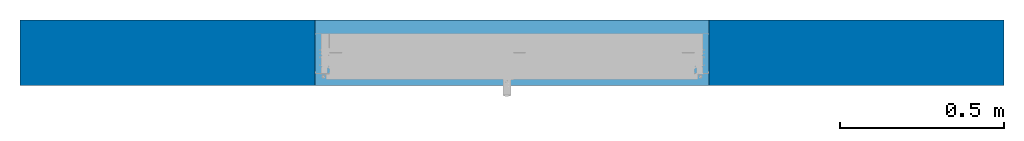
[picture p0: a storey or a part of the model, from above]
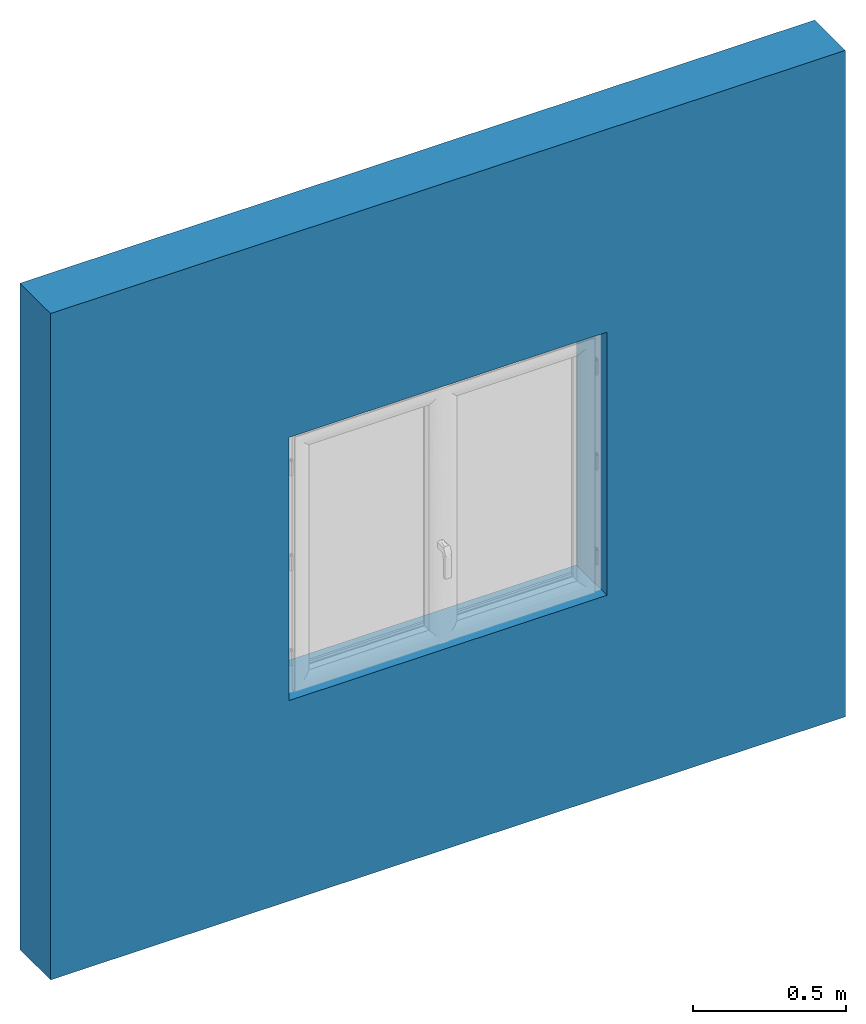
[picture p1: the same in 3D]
Properties of the parts of a building model (IFC2X3)

# File
Description: ViewDefinition [CoordinationView]
Time: 2016-06-16T14:24:24
Written by: Autodesk Revit Architecture 2011 - 1.0
Made in: 20100326_1700(x64)

# IfcSite, 默认
RefLatitude: 42, 24, 53, 508911; RefLongitude: -71, -15, -29, -58837; RefElevation: 0 mm

# IfcBuilding
Pset_BuildingCommon - NumberOfStoreys: 1

# IfcBuildingStorey, Level 1
Elevation: 0 mm
PSet_Revit_标识数据 - 名称: Level 1
PSet_Revit_限制条件 - 立面: 0 mm
PSet_Revit_Type_图形 - 线宽: 1; 颜色: 0; 线型图案: 实心; 端点 1 处的默认符号: no; 端点 2 处的默认符号: yes
PSet_Revit_Type_限制条件 - 基面: 0
PSet_Revit_Type_尺寸标注 - 自动计算房间高度: yes

# IfcWallStandardCase: 基本墙:Wall 1:1320, 基本墙:Wall 1:13409
In: Level 1
Material: 4ITR-20-4 argon inter TGI 200 mm
Pset_WallCommon - Reference: 基本墙:Wall 1; LoadBearing: no; ExtendToStructure: no; IsExternal: yes
PSet_Revit_限制条件 - 定位线: 0; 基准限制条件: Level 1; 底部偏移: 0 mm; 已附着底部: no; 底部延伸距离: 0 mm; 无连接高度: 2659.66 mm; 顶部偏移: 0 mm; 已附着顶部: no; 顶部延伸距离: 0 mm; 房间边界: yes; 与体量相关: no
PSet_Revit_阶段化 - 创建的阶段: New Construction
PSet_Revit_结构 - 结构用途: 0
PSet_Revit_尺寸标注 - 长度: 3000 mm; 面积: 6718965 mm2; 体积: 1343793021 mm3
PSet_Revit_Type_构造 - 在插入点包络: 0; 在端点包络: 0; 宽度: 200 mm; 功能: 1
PSet_Revit_Type_图形 - 粗略比例填充颜色: 0

# IfcWindow: Fenêtre 2 vantaux 1050 x 1200 mm Claire, Huet Fenêtre 2 vantaux Stylium:Fenêtre 2 vantaux 1050 x 1200 mm Claire:Fenêtre 2 vantaux 1050 x 1200 mm Claire:18678
In: Level 1
Type - ParameterTakesPrecedence: no; Sizeable: no
OverallHeight: 1050 mm; OverallWidth: 1200 mm
Pset_WindowCommon - Reference: Huet Fenêtre 2 vantaux Stylium:Fenêtre 2 vantaux 1050 x 1200 mm Claire; IsExternal: yes
PSet_Revit_限制条件 - 标高: Level 1; 底高度: 800 mm
PSet_Revit_其他 - 顶高度: 1850 mm
PSet_Revit_标识数据 - 标记: 1
PSet_Revit_阶段化 - 创建的阶段: New Construction
PSet_Revit_Type_分析模型 - Uw: 1,5; Ug: 1,1; Tlw: 0,54; Condition été Sw: 0,42; Condition été Sw1: 0,39; Condition été Sw2: 0,03; Condition été Sw3: 0,00; Condition hiver Sw: 0,42; Condition hiver Sw1: 0,39; Condition hiver Sw2: 0,03; Condition hiver Sw3: 0,00
PSet_Revit_Type_标识数据 - URL: www.huet.fr; Tél.: 00 33 (0)2 28 12 04 20; 类型注释: Fabriquant de Menuiseries Exterieures, HUET vous offre une large gamme de Fenetres et Porte-Fenetres permettant d’appréhender les différents segments de marché.; Personnalisation: Elargisseur serrure anodisé ou couleur de menuiserie; 型号: Fenêtre 2 vantaux Stylium; 制造商: Huet; Fax: 02 51 49 19 00; 说明: Tous les types d'ouvertures en fenêtre et porte fenêtre pour tous vos projets; Adresse: 30 rue Pauline de Lezardière 85300 Challans; 类型标记: 16
PSet_Revit_Type_材质和装饰 - Poignée: Huet gris anodisé; Couleur de la menuiserie: Claire; Cadre: Huet RAL 7016; Vitrage: 4ITR-20-4 argon inter TGI
PSet_Revit_Type_尺寸标注 - 高度: 1050 mm; 宽度: 1200 mm
PSet_Revit_Type_限制条件 - Minimal Width: 400 mm; Minimal Height: 400 mm; Maximal Width: 6000 mm; Maximal Height: 6000 mm
PSet_Revit_Type_其他 - Default Sill Height: 800 mm; Actual Width: 1200 mm; Actual Height: 1050 mm
PSet_Revit_Type_构造 - 墙闭合: 0
